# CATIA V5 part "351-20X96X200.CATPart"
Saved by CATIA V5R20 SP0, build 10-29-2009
Part number: 351-20X96X200
Definition: NONE
Nomenclature: 351-20X96X200
Source: Unknown
Description: 351-20X96X200
Bounding box of the stored display mesh (mm): x -6 to 194, y -16 to 16, z -16 to 16
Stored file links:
  C:\Users\Utente\Desktop\IO LAVORO\3D X SITO CF\X SITO\PLASTICA\351\351-20X96X200.CATPart

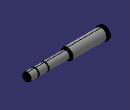
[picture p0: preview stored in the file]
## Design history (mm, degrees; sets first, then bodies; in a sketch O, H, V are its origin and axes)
Body1 "351-20X96X200" (main body)
  Solid1: solid without history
